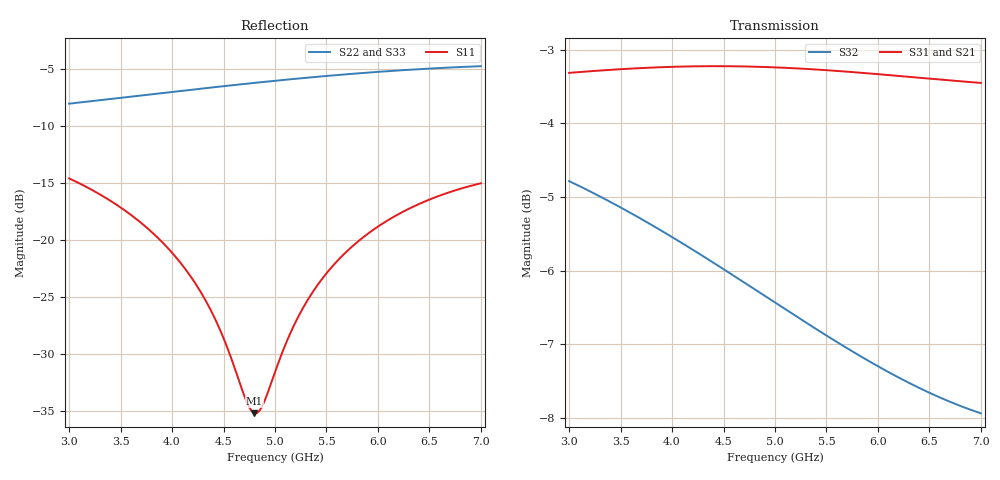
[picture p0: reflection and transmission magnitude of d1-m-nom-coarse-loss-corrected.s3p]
! yapnr Order 0 prediction d1-m-nom-coarse: predictions/D1/variants/d1-star-m-nom/coarse_dense.s3p, loss-corrected
! substrate M-nom; coupon model OSHPARK-4L-FR408HR; correction: ratio (port line)
! |S21|, |S31| (and S12, S13) scaled, phases kept; 50 ohm, e^(+jwt)
# GHz S RI R 50
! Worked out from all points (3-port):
!   161 points, 3 GHz to 7 GHz, reference 50 ohm
!   strongest paths, dB at 3 GHz, 4 GHz, 5 GHz, 6 GHz, 7 GHz:
!     S31: -3.3, -3.2, -3.2, -3.3, -3.5
!     S21: -3.3, -3.2, -3.2, -3.3, -3.5
!     S32: -4.8, -5.5, -6.4, -7.3, -7.9
!   lowest |S11| = -35.2 dB at 4.8 GHz (marker M1), VSWR 1.04, Z = 51.7 - j0.368 ohm
!   |S11| at or under -10 dB: start of sweep to end of sweep
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3  -0.0727 0.1715  0.0993 -0.6755  0.0993 -0.6755
   0.0993 -0.6755  0.142 0.3692  -0.1539 -0.5555
   0.0993 -0.6755  -0.1539 -0.5555  0.142 0.3692
3.625  -0.0128 0.1258  -0.1115 -0.6784  -0.1115 -0.6784
       -0.1116 -0.6783  0.2805 0.3203  -0.3249 -0.4401
       -0.1116 -0.6783  -0.3249 -0.4401  0.2805 0.3203
4.1  0.0144 0.0763  -0.2686 -0.6351  -0.2686 -0.6351
     -0.2686 -0.635  0.3733 0.2522  -0.4116 -0.3226
     -0.2686 -0.635  -0.4116 -0.3226  0.3733 0.2522
4.4  0.0212 0.0419  -0.361 -0.588  -0.361 -0.588
     -0.3609 -0.588  0.423 0.1967  -0.4457 -0.2426
     -0.3609 -0.588  -0.4457 -0.2426  0.423 0.1967
4.8  0.0171 -0.00356  -0.4706 -0.5038  -0.4706 -0.5038
     -0.4706 -0.5037  0.4752 0.1101  -0.4675 -0.1357
     -0.4706 -0.5037  -0.4675 -0.1357  0.4752 0.1101
5  0.00951 -0.0246  -0.5182 -0.4536  -0.5182 -0.4536
   -0.5182 -0.4535  0.4943 0.0624  -0.4693 -0.0839
   -0.5182 -0.4535  -0.4693 -0.0839  0.4943 0.0624
5.3  -0.00795 -0.0524  -0.5789 -0.37  -0.5789 -0.37
     -0.5789 -0.3699  0.5132 -0.0132  -0.462 -0.0102
     -0.5789 -0.3699  -0.462 -0.0102  0.5132 -0.0132
5.725  -0.0428 -0.081  -0.6409 -0.2388  -0.6409 -0.2388
       -0.6408 -0.2387  0.5186 -0.1247  -0.4348 0.0837
       -0.6408 -0.2387  -0.4348 0.0837  0.5186 -0.1247
6.3  -0.0998 -0.094  -0.6769 -0.0487  -0.6769 -0.0487
     -0.6768 -0.0487  0.4851 -0.273  -0.3758 0.1886
     -0.6768 -0.0487  -0.3758 0.1886  0.4851 -0.273
7  -0.164 -0.0672  -0.6476 0.1801  -0.6476 0.1801
   -0.6475 0.1801  0.3869 -0.4285  -0.2839 0.283
   -0.6475 0.1801  -0.2839 0.283  0.3869 -0.4285
